VERSION 5.8 ;
BUSBITCHARS "[]" ;
DIVIDERCHAR "/" ;
UNITS
    DATABASE MICRONS 1000 ;
END UNITS

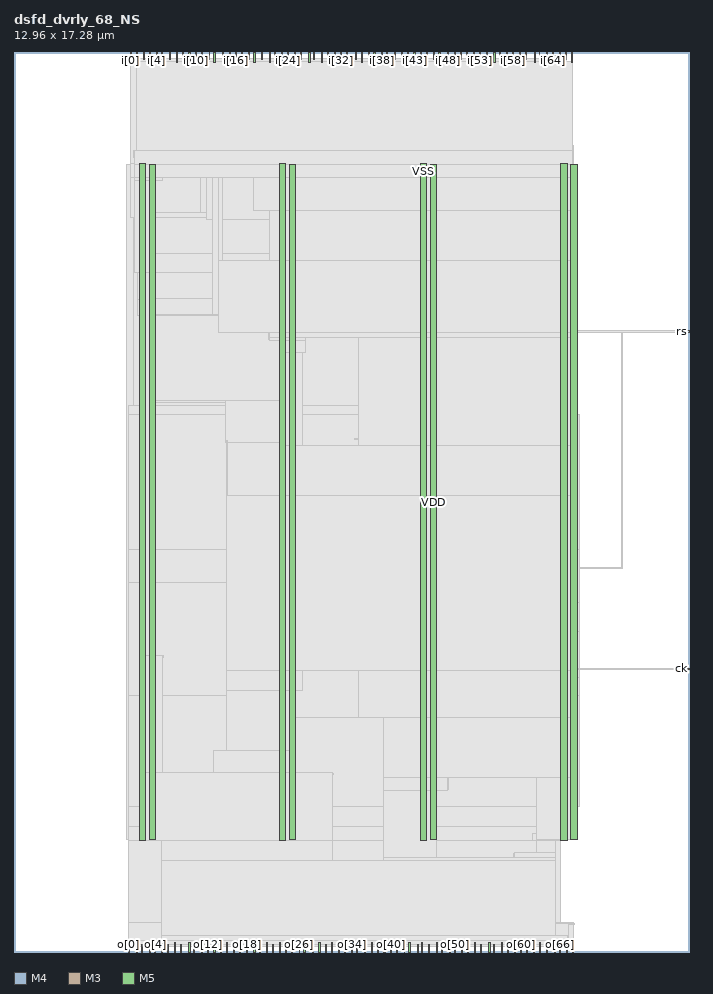
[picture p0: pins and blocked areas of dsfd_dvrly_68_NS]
MACRO dsfd_dvrly_68_NS
  FOREIGN dsfd_dvrly_68_NS 0 0 ;
  CLASS BLOCK ;
  SIZE 12.96 BY 17.28 ;
  PIN ck
    DIRECTION INPUT ;
    USE SIGNAL ;
    PORT
      LAYER M4 ;
        RECT  12.768 5.424 12.96 5.448 ;
    END
  END ck
  PIN ck_o
    DIRECTION OUTPUT ;
    USE SIGNAL ;
    PORT
      LAYER M3 ;
        RECT  10.728 0 10.746 0.144 ;
    END
  END ck_o
  PIN i[0]
    DIRECTION INPUT ;
    USE SIGNAL ;
    PORT
      LAYER M3 ;
        RECT  2.232 17.136 2.25 17.28 ;
    END
  END i[0]
  PIN i[10]
    DIRECTION INPUT ;
    USE SIGNAL ;
    PORT
      LAYER M3 ;
        RECT  3.492 17.136 3.51 17.28 ;
    END
  END i[10]
  PIN i[11]
    DIRECTION INPUT ;
    USE SIGNAL ;
    PORT
      LAYER M5 ;
        RECT  3.6 17.088 3.624 17.28 ;
    END
  END i[11]
  PIN i[12]
    DIRECTION INPUT ;
    USE SIGNAL ;
    PORT
      LAYER M3 ;
        RECT  3.744 17.136 3.762 17.28 ;
    END
  END i[12]
  PIN i[13]
    DIRECTION INPUT ;
    USE SIGNAL ;
    PORT
      LAYER M5 ;
        RECT  3.84 17.088 3.864 17.28 ;
    END
  END i[13]
  PIN i[14]
    DIRECTION INPUT ;
    USE SIGNAL ;
    PORT
      LAYER M3 ;
        RECT  3.996 17.136 4.014 17.28 ;
    END
  END i[14]
  PIN i[15]
    DIRECTION INPUT ;
    USE SIGNAL ;
    PORT
      LAYER M5 ;
        RECT  4.128 17.088 4.152 17.28 ;
    END
  END i[15]
  PIN i[16]
    DIRECTION INPUT ;
    USE SIGNAL ;
    PORT
      LAYER M3 ;
        RECT  4.248 17.136 4.266 17.28 ;
    END
  END i[16]
  PIN i[17]
    DIRECTION INPUT ;
    USE SIGNAL ;
    PORT
      LAYER M5 ;
        RECT  4.368 17.088 4.392 17.28 ;
    END
  END i[17]
  PIN i[18]
    DIRECTION INPUT ;
    USE SIGNAL ;
    PORT
      LAYER M3 ;
        RECT  4.5 17.136 4.518 17.28 ;
    END
  END i[18]
  PIN i[19]
    DIRECTION INPUT ;
    USE SIGNAL ;
    PORT
      LAYER M5 ;
        RECT  4.608 17.088 4.632 17.28 ;
    END
  END i[19]
  PIN i[1]
    DIRECTION INPUT ;
    USE SIGNAL ;
    PORT
      LAYER M5 ;
        RECT  2.352 17.088 2.376 17.28 ;
    END
  END i[1]
  PIN i[20]
    DIRECTION INPUT ;
    USE SIGNAL ;
    PORT
      LAYER M3 ;
        RECT  4.752 17.136 4.77 17.28 ;
    END
  END i[20]
  PIN i[21]
    DIRECTION INPUT ;
    USE SIGNAL ;
    PORT
      LAYER M5 ;
        RECT  4.896 17.088 4.92 17.28 ;
    END
  END i[21]
  PIN i[22]
    DIRECTION INPUT ;
    USE SIGNAL ;
    PORT
      LAYER M3 ;
        RECT  5.004 17.136 5.022 17.28 ;
    END
  END i[22]
  PIN i[23]
    DIRECTION INPUT ;
    USE SIGNAL ;
    PORT
      LAYER M5 ;
        RECT  5.136 17.088 5.16 17.28 ;
    END
  END i[23]
  PIN i[24]
    DIRECTION INPUT ;
    USE SIGNAL ;
    PORT
      LAYER M3 ;
        RECT  5.256 17.136 5.274 17.28 ;
    END
  END i[24]
  PIN i[25]
    DIRECTION INPUT ;
    USE SIGNAL ;
    PORT
      LAYER M5 ;
        RECT  5.376 17.088 5.4 17.28 ;
    END
  END i[25]
  PIN i[26]
    DIRECTION INPUT ;
    USE SIGNAL ;
    PORT
      LAYER M3 ;
        RECT  5.508 17.136 5.526 17.28 ;
    END
  END i[26]
  PIN i[27]
    DIRECTION INPUT ;
    USE SIGNAL ;
    PORT
      LAYER M5 ;
        RECT  5.664 17.088 5.688 17.28 ;
    END
  END i[27]
  PIN i[28]
    DIRECTION INPUT ;
    USE SIGNAL ;
    PORT
      LAYER M3 ;
        RECT  5.76 17.136 5.778 17.28 ;
    END
  END i[28]
  PIN i[29]
    DIRECTION INPUT ;
    USE SIGNAL ;
    PORT
      LAYER M5 ;
        RECT  5.904 17.088 5.928 17.28 ;
    END
  END i[29]
  PIN i[2]
    DIRECTION INPUT ;
    USE SIGNAL ;
    PORT
      LAYER M3 ;
        RECT  2.484 17.136 2.502 17.28 ;
    END
  END i[2]
  PIN i[30]
    DIRECTION INPUT ;
    USE SIGNAL ;
    PORT
      LAYER M3 ;
        RECT  6.012 17.136 6.03 17.28 ;
    END
  END i[30]
  PIN i[31]
    DIRECTION INPUT ;
    USE SIGNAL ;
    PORT
      LAYER M5 ;
        RECT  6.144 17.088 6.168 17.28 ;
    END
  END i[31]
  PIN i[32]
    DIRECTION INPUT ;
    USE SIGNAL ;
    PORT
      LAYER M3 ;
        RECT  6.264 17.136 6.282 17.28 ;
    END
  END i[32]
  PIN i[33]
    DIRECTION INPUT ;
    USE SIGNAL ;
    PORT
      LAYER M5 ;
        RECT  6.384 17.088 6.408 17.28 ;
    END
  END i[33]
  PIN i[34]
    DIRECTION INPUT ;
    USE SIGNAL ;
    PORT
      LAYER M3 ;
        RECT  6.552 17.136 6.57 17.28 ;
    END
  END i[34]
  PIN i[35]
    DIRECTION INPUT ;
    USE SIGNAL ;
    PORT
      LAYER M5 ;
        RECT  6.672 17.088 6.696 17.28 ;
    END
  END i[35]
  PIN i[36]
    DIRECTION INPUT ;
    USE SIGNAL ;
    PORT
      LAYER M3 ;
        RECT  6.804 17.136 6.822 17.28 ;
    END
  END i[36]
  PIN i[37]
    DIRECTION INPUT ;
    USE SIGNAL ;
    PORT
      LAYER M5 ;
        RECT  6.912 17.088 6.936 17.28 ;
    END
  END i[37]
  PIN i[38]
    DIRECTION INPUT ;
    USE SIGNAL ;
    PORT
      LAYER M3 ;
        RECT  7.056 17.136 7.074 17.28 ;
    END
  END i[38]
  PIN i[39]
    DIRECTION INPUT ;
    USE SIGNAL ;
    PORT
      LAYER M5 ;
        RECT  7.152 17.088 7.176 17.28 ;
    END
  END i[39]
  PIN i[3]
    DIRECTION INPUT ;
    USE SIGNAL ;
    PORT
      LAYER M5 ;
        RECT  2.592 17.088 2.616 17.28 ;
    END
  END i[3]
  PIN i[40]
    DIRECTION INPUT ;
    USE SIGNAL ;
    PORT
      LAYER M3 ;
        RECT  7.308 17.136 7.326 17.28 ;
    END
  END i[40]
  PIN i[41]
    DIRECTION INPUT ;
    USE SIGNAL ;
    PORT
      LAYER M5 ;
        RECT  7.44 17.088 7.464 17.28 ;
    END
  END i[41]
  PIN i[42]
    DIRECTION INPUT ;
    USE SIGNAL ;
    PORT
      LAYER M3 ;
        RECT  7.56 17.136 7.578 17.28 ;
    END
  END i[42]
  PIN i[43]
    DIRECTION INPUT ;
    USE SIGNAL ;
    PORT
      LAYER M5 ;
        RECT  7.68 17.088 7.704 17.28 ;
    END
  END i[43]
  PIN i[44]
    DIRECTION INPUT ;
    USE SIGNAL ;
    PORT
      LAYER M3 ;
        RECT  7.812 17.136 7.83 17.28 ;
    END
  END i[44]
  PIN i[45]
    DIRECTION INPUT ;
    USE SIGNAL ;
    PORT
      LAYER M5 ;
        RECT  7.92 17.088 7.944 17.28 ;
    END
  END i[45]
  PIN i[46]
    DIRECTION INPUT ;
    USE SIGNAL ;
    PORT
      LAYER M3 ;
        RECT  8.064 17.136 8.082 17.28 ;
    END
  END i[46]
  PIN i[47]
    DIRECTION INPUT ;
    USE SIGNAL ;
    PORT
      LAYER M5 ;
        RECT  8.16 17.088 8.184 17.28 ;
    END
  END i[47]
  PIN i[48]
    DIRECTION INPUT ;
    USE SIGNAL ;
    PORT
      LAYER M3 ;
        RECT  8.316 17.136 8.334 17.28 ;
    END
  END i[48]
  PIN i[49]
    DIRECTION INPUT ;
    USE SIGNAL ;
    PORT
      LAYER M5 ;
        RECT  8.448 17.088 8.472 17.28 ;
    END
  END i[49]
  PIN i[4]
    DIRECTION INPUT ;
    USE SIGNAL ;
    PORT
      LAYER M3 ;
        RECT  2.736 17.136 2.754 17.28 ;
    END
  END i[4]
  PIN i[50]
    DIRECTION INPUT ;
    USE SIGNAL ;
    PORT
      LAYER M3 ;
        RECT  8.568 17.136 8.586 17.28 ;
    END
  END i[50]
  PIN i[51]
    DIRECTION INPUT ;
    USE SIGNAL ;
    PORT
      LAYER M5 ;
        RECT  8.688 17.088 8.712 17.28 ;
    END
  END i[51]
  PIN i[52]
    DIRECTION INPUT ;
    USE SIGNAL ;
    PORT
      LAYER M3 ;
        RECT  8.82 17.136 8.838 17.28 ;
    END
  END i[52]
  PIN i[53]
    DIRECTION INPUT ;
    USE SIGNAL ;
    PORT
      LAYER M5 ;
        RECT  8.928 17.088 8.952 17.28 ;
    END
  END i[53]
  PIN i[54]
    DIRECTION INPUT ;
    USE SIGNAL ;
    PORT
      LAYER M3 ;
        RECT  9.072 17.136 9.09 17.28 ;
    END
  END i[54]
  PIN i[55]
    DIRECTION INPUT ;
    USE SIGNAL ;
    PORT
      LAYER M5 ;
        RECT  9.216 17.088 9.24 17.28 ;
    END
  END i[55]
  PIN i[56]
    DIRECTION INPUT ;
    USE SIGNAL ;
    PORT
      LAYER M3 ;
        RECT  9.324 17.136 9.342 17.28 ;
    END
  END i[56]
  PIN i[57]
    DIRECTION INPUT ;
    USE SIGNAL ;
    PORT
      LAYER M5 ;
        RECT  9.456 17.088 9.48 17.28 ;
    END
  END i[57]
  PIN i[58]
    DIRECTION INPUT ;
    USE SIGNAL ;
    PORT
      LAYER M3 ;
        RECT  9.576 17.136 9.594 17.28 ;
    END
  END i[58]
  PIN i[59]
    DIRECTION INPUT ;
    USE SIGNAL ;
    PORT
      LAYER M5 ;
        RECT  9.696 17.088 9.72 17.28 ;
    END
  END i[59]
  PIN i[5]
    DIRECTION INPUT ;
    USE SIGNAL ;
    PORT
      LAYER M5 ;
        RECT  2.832 17.088 2.856 17.28 ;
    END
  END i[5]
  PIN i[60]
    DIRECTION INPUT ;
    USE SIGNAL ;
    PORT
      LAYER M3 ;
        RECT  9.828 17.136 9.846 17.28 ;
    END
  END i[60]
  PIN i[61]
    DIRECTION INPUT ;
    USE SIGNAL ;
    PORT
      LAYER M5 ;
        RECT  9.984 17.088 10.008 17.28 ;
    END
  END i[61]
  PIN i[62]
    DIRECTION INPUT ;
    USE SIGNAL ;
    PORT
      LAYER M3 ;
        RECT  10.08 17.136 10.098 17.28 ;
    END
  END i[62]
  PIN i[63]
    DIRECTION INPUT ;
    USE SIGNAL ;
    PORT
      LAYER M5 ;
        RECT  10.224 17.088 10.248 17.28 ;
    END
  END i[63]
  PIN i[64]
    DIRECTION INPUT ;
    USE SIGNAL ;
    PORT
      LAYER M3 ;
        RECT  10.332 17.136 10.35 17.28 ;
    END
  END i[64]
  PIN i[65]
    DIRECTION INPUT ;
    USE SIGNAL ;
    PORT
      LAYER M5 ;
        RECT  10.464 17.088 10.488 17.28 ;
    END
  END i[65]
  PIN i[66]
    DIRECTION INPUT ;
    USE SIGNAL ;
    PORT
      LAYER M3 ;
        RECT  10.584 17.136 10.602 17.28 ;
    END
  END i[66]
  PIN i[67]
    DIRECTION INPUT ;
    USE SIGNAL ;
    PORT
      LAYER M5 ;
        RECT  10.704 17.088 10.728 17.28 ;
    END
  END i[67]
  PIN i[6]
    DIRECTION INPUT ;
    USE SIGNAL ;
    PORT
      LAYER M3 ;
        RECT  2.988 17.136 3.006 17.28 ;
    END
  END i[6]
  PIN i[7]
    DIRECTION INPUT ;
    USE SIGNAL ;
    PORT
      LAYER M5 ;
        RECT  3.12 17.088 3.144 17.28 ;
    END
  END i[7]
  PIN i[8]
    DIRECTION INPUT ;
    USE SIGNAL ;
    PORT
      LAYER M3 ;
        RECT  3.24 17.136 3.258 17.28 ;
    END
  END i[8]
  PIN i[9]
    DIRECTION INPUT ;
    USE SIGNAL ;
    PORT
      LAYER M5 ;
        RECT  3.36 17.088 3.384 17.28 ;
    END
  END i[9]
  PIN o[0]
    DIRECTION OUTPUT ;
    USE SIGNAL ;
    PORT
      LAYER M3 ;
        RECT  2.196 0 2.214 0.144 ;
    END
  END o[0]
  PIN o[10]
    DIRECTION OUTPUT ;
    USE SIGNAL ;
    PORT
      LAYER M3 ;
        RECT  3.456 0 3.474 0.144 ;
    END
  END o[10]
  PIN o[11]
    DIRECTION OUTPUT ;
    USE SIGNAL ;
    PORT
      LAYER M5 ;
        RECT  3.6 0 3.624 0.192 ;
    END
  END o[11]
  PIN o[12]
    DIRECTION OUTPUT ;
    USE SIGNAL ;
    PORT
      LAYER M3 ;
        RECT  3.708 0 3.726 0.144 ;
    END
  END o[12]
  PIN o[13]
    DIRECTION OUTPUT ;
    USE SIGNAL ;
    PORT
      LAYER M5 ;
        RECT  3.84 0 3.864 0.192 ;
    END
  END o[13]
  PIN o[14]
    DIRECTION OUTPUT ;
    USE SIGNAL ;
    PORT
      LAYER M3 ;
        RECT  3.96 0 3.978 0.144 ;
    END
  END o[14]
  PIN o[15]
    DIRECTION OUTPUT ;
    USE SIGNAL ;
    PORT
      LAYER M5 ;
        RECT  4.08 0 4.104 0.192 ;
    END
  END o[15]
  PIN o[16]
    DIRECTION OUTPUT ;
    USE SIGNAL ;
    PORT
      LAYER M3 ;
        RECT  4.212 0 4.23 0.144 ;
    END
  END o[16]
  PIN o[17]
    DIRECTION OUTPUT ;
    USE SIGNAL ;
    PORT
      LAYER M5 ;
        RECT  4.32 0 4.344 0.192 ;
    END
  END o[17]
  PIN o[18]
    DIRECTION OUTPUT ;
    USE SIGNAL ;
    PORT
      LAYER M3 ;
        RECT  4.464 0 4.482 0.144 ;
    END
  END o[18]
  PIN o[19]
    DIRECTION OUTPUT ;
    USE SIGNAL ;
    PORT
      LAYER M5 ;
        RECT  4.608 0 4.632 0.192 ;
    END
  END o[19]
  PIN o[1]
    DIRECTION OUTPUT ;
    USE SIGNAL ;
    PORT
      LAYER M5 ;
        RECT  2.352 0 2.376 0.192 ;
    END
  END o[1]
  PIN o[20]
    DIRECTION OUTPUT ;
    USE SIGNAL ;
    PORT
      LAYER M3 ;
        RECT  4.716 0 4.734 0.144 ;
    END
  END o[20]
  PIN o[21]
    DIRECTION OUTPUT ;
    USE SIGNAL ;
    PORT
      LAYER M5 ;
        RECT  4.848 0 4.872 0.192 ;
    END
  END o[21]
  PIN o[22]
    DIRECTION OUTPUT ;
    USE SIGNAL ;
    PORT
      LAYER M3 ;
        RECT  4.968 0 4.986 0.144 ;
    END
  END o[22]
  PIN o[23]
    DIRECTION OUTPUT ;
    USE SIGNAL ;
    PORT
      LAYER M5 ;
        RECT  5.088 0 5.112 0.192 ;
    END
  END o[23]
  PIN o[24]
    DIRECTION OUTPUT ;
    USE SIGNAL ;
    PORT
      LAYER M3 ;
        RECT  5.22 0 5.238 0.144 ;
    END
  END o[24]
  PIN o[25]
    DIRECTION OUTPUT ;
    USE SIGNAL ;
    PORT
      LAYER M5 ;
        RECT  5.328 0 5.352 0.192 ;
    END
  END o[25]
  PIN o[26]
    DIRECTION OUTPUT ;
    USE SIGNAL ;
    PORT
      LAYER M3 ;
        RECT  5.472 0 5.49 0.144 ;
    END
  END o[26]
  PIN o[27]
    DIRECTION OUTPUT ;
    USE SIGNAL ;
    PORT
      LAYER M5 ;
        RECT  5.568 0 5.592 0.192 ;
    END
  END o[27]
  PIN o[28]
    DIRECTION OUTPUT ;
    USE SIGNAL ;
    PORT
      LAYER M3 ;
        RECT  5.724 0 5.742 0.144 ;
    END
  END o[28]
  PIN o[29]
    DIRECTION OUTPUT ;
    USE SIGNAL ;
    PORT
      LAYER M5 ;
        RECT  5.856 0 5.88 0.192 ;
    END
  END o[29]
  PIN o[2]
    DIRECTION OUTPUT ;
    USE SIGNAL ;
    PORT
      LAYER M3 ;
        RECT  2.448 0 2.466 0.144 ;
    END
  END o[2]
  PIN o[30]
    DIRECTION OUTPUT ;
    USE SIGNAL ;
    PORT
      LAYER M3 ;
        RECT  5.976 0 5.994 0.144 ;
    END
  END o[30]
  PIN o[31]
    DIRECTION OUTPUT ;
    USE SIGNAL ;
    PORT
      LAYER M5 ;
        RECT  6.096 0 6.12 0.192 ;
    END
  END o[31]
  PIN o[32]
    DIRECTION OUTPUT ;
    USE SIGNAL ;
    PORT
      LAYER M3 ;
        RECT  6.228 0 6.246 0.144 ;
    END
  END o[32]
  PIN o[33]
    DIRECTION OUTPUT ;
    USE SIGNAL ;
    PORT
      LAYER M5 ;
        RECT  6.336 0 6.36 0.192 ;
    END
  END o[33]
  PIN o[34]
    DIRECTION OUTPUT ;
    USE SIGNAL ;
    PORT
      LAYER M3 ;
        RECT  6.48 0 6.498 0.144 ;
    END
  END o[34]
  PIN o[35]
    DIRECTION OUTPUT ;
    USE SIGNAL ;
    PORT
      LAYER M5 ;
        RECT  6.576 0 6.6 0.192 ;
    END
  END o[35]
  PIN o[36]
    DIRECTION OUTPUT ;
    USE SIGNAL ;
    PORT
      LAYER M3 ;
        RECT  6.732 0 6.75 0.144 ;
    END
  END o[36]
  PIN o[37]
    DIRECTION OUTPUT ;
    USE SIGNAL ;
    PORT
      LAYER M5 ;
        RECT  6.864 0 6.888 0.192 ;
    END
  END o[37]
  PIN o[38]
    DIRECTION OUTPUT ;
    USE SIGNAL ;
    PORT
      LAYER M3 ;
        RECT  6.984 0 7.002 0.144 ;
    END
  END o[38]
  PIN o[39]
    DIRECTION OUTPUT ;
    USE SIGNAL ;
    PORT
      LAYER M5 ;
        RECT  7.104 0 7.128 0.192 ;
    END
  END o[39]
  PIN o[3]
    DIRECTION OUTPUT ;
    USE SIGNAL ;
    PORT
      LAYER M5 ;
        RECT  2.592 0 2.616 0.192 ;
    END
  END o[3]
  PIN o[40]
    DIRECTION OUTPUT ;
    USE SIGNAL ;
    PORT
      LAYER M3 ;
        RECT  7.236 0 7.254 0.144 ;
    END
  END o[40]
  PIN o[41]
    DIRECTION OUTPUT ;
    USE SIGNAL ;
    PORT
      LAYER M5 ;
        RECT  7.344 0 7.368 0.192 ;
    END
  END o[41]
  PIN o[42]
    DIRECTION OUTPUT ;
    USE SIGNAL ;
    PORT
      LAYER M3 ;
        RECT  7.488 0 7.506 0.144 ;
    END
  END o[42]
  PIN o[43]
    DIRECTION OUTPUT ;
    USE SIGNAL ;
    PORT
      LAYER M5 ;
        RECT  7.584 0 7.608 0.192 ;
    END
  END o[43]
  PIN o[44]
    DIRECTION OUTPUT ;
    USE SIGNAL ;
    PORT
      LAYER M3 ;
        RECT  7.74 0 7.758 0.144 ;
    END
  END o[44]
  PIN o[45]
    DIRECTION OUTPUT ;
    USE SIGNAL ;
    PORT
      LAYER M5 ;
        RECT  7.824 0 7.848 0.192 ;
    END
  END o[45]
  PIN o[46]
    DIRECTION OUTPUT ;
    USE SIGNAL ;
    PORT
      LAYER M3 ;
        RECT  7.956 0 7.974 0.144 ;
    END
  END o[46]
  PIN o[47]
    DIRECTION OUTPUT ;
    USE SIGNAL ;
    PORT
      LAYER M5 ;
        RECT  8.112 0 8.136 0.192 ;
    END
  END o[47]
  PIN o[48]
    DIRECTION OUTPUT ;
    USE SIGNAL ;
    PORT
      LAYER M3 ;
        RECT  8.208 0 8.226 0.144 ;
    END
  END o[48]
  PIN o[49]
    DIRECTION OUTPUT ;
    USE SIGNAL ;
    PORT
      LAYER M5 ;
        RECT  8.352 0 8.376 0.192 ;
    END
  END o[49]
  PIN o[4]
    DIRECTION OUTPUT ;
    USE SIGNAL ;
    PORT
      LAYER M3 ;
        RECT  2.7 0 2.718 0.144 ;
    END
  END o[4]
  PIN o[50]
    DIRECTION OUTPUT ;
    USE SIGNAL ;
    PORT
      LAYER M3 ;
        RECT  8.46 0 8.478 0.144 ;
    END
  END o[50]
  PIN o[51]
    DIRECTION OUTPUT ;
    USE SIGNAL ;
    PORT
      LAYER M5 ;
        RECT  8.592 0 8.616 0.192 ;
    END
  END o[51]
  PIN o[52]
    DIRECTION OUTPUT ;
    USE SIGNAL ;
    PORT
      LAYER M3 ;
        RECT  8.712 0 8.73 0.144 ;
    END
  END o[52]
  PIN o[53]
    DIRECTION OUTPUT ;
    USE SIGNAL ;
    PORT
      LAYER M5 ;
        RECT  8.832 0 8.856 0.192 ;
    END
  END o[53]
  PIN o[54]
    DIRECTION OUTPUT ;
    USE SIGNAL ;
    PORT
      LAYER M3 ;
        RECT  8.964 0 8.982 0.144 ;
    END
  END o[54]
  PIN o[55]
    DIRECTION OUTPUT ;
    USE SIGNAL ;
    PORT
      LAYER M5 ;
        RECT  9.12 0 9.144 0.192 ;
    END
  END o[55]
  PIN o[56]
    DIRECTION OUTPUT ;
    USE SIGNAL ;
    PORT
      LAYER M3 ;
        RECT  9.216 0 9.234 0.144 ;
    END
  END o[56]
  PIN o[57]
    DIRECTION OUTPUT ;
    USE SIGNAL ;
    PORT
      LAYER M5 ;
        RECT  9.36 0 9.384 0.192 ;
    END
  END o[57]
  PIN o[58]
    DIRECTION OUTPUT ;
    USE SIGNAL ;
    PORT
      LAYER M3 ;
        RECT  9.468 0 9.486 0.144 ;
    END
  END o[58]
  PIN o[59]
    DIRECTION OUTPUT ;
    USE SIGNAL ;
    PORT
      LAYER M5 ;
        RECT  9.6 0 9.624 0.192 ;
    END
  END o[59]
  PIN o[5]
    DIRECTION OUTPUT ;
    USE SIGNAL ;
    PORT
      LAYER M5 ;
        RECT  2.832 0 2.856 0.192 ;
    END
  END o[5]
  PIN o[60]
    DIRECTION OUTPUT ;
    USE SIGNAL ;
    PORT
      LAYER M3 ;
        RECT  9.72 0 9.738 0.144 ;
    END
  END o[60]
  PIN o[61]
    DIRECTION OUTPUT ;
    USE SIGNAL ;
    PORT
      LAYER M5 ;
        RECT  9.84 0 9.864 0.192 ;
    END
  END o[61]
  PIN o[62]
    DIRECTION OUTPUT ;
    USE SIGNAL ;
    PORT
      LAYER M3 ;
        RECT  9.972 0 9.99 0.144 ;
    END
  END o[62]
  PIN o[63]
    DIRECTION OUTPUT ;
    USE SIGNAL ;
    PORT
      LAYER M5 ;
        RECT  10.08 0 10.104 0.192 ;
    END
  END o[63]
  PIN o[64]
    DIRECTION OUTPUT ;
    USE SIGNAL ;
    PORT
      LAYER M3 ;
        RECT  10.224 0 10.242 0.144 ;
    END
  END o[64]
  PIN o[65]
    DIRECTION OUTPUT ;
    USE SIGNAL ;
    PORT
      LAYER M5 ;
        RECT  10.368 0 10.392 0.192 ;
    END
  END o[65]
  PIN o[66]
    DIRECTION OUTPUT ;
    USE SIGNAL ;
    PORT
      LAYER M3 ;
        RECT  10.476 0 10.494 0.144 ;
    END
  END o[66]
  PIN o[67]
    DIRECTION OUTPUT ;
    USE SIGNAL ;
    PORT
      LAYER M5 ;
        RECT  10.608 0 10.632 0.192 ;
    END
  END o[67]
  PIN o[6]
    DIRECTION OUTPUT ;
    USE SIGNAL ;
    PORT
      LAYER M3 ;
        RECT  2.952 0 2.97 0.144 ;
    END
  END o[6]
  PIN o[7]
    DIRECTION OUTPUT ;
    USE SIGNAL ;
    PORT
      LAYER M5 ;
        RECT  3.072 0 3.096 0.192 ;
    END
  END o[7]
  PIN o[8]
    DIRECTION OUTPUT ;
    USE SIGNAL ;
    PORT
      LAYER M3 ;
        RECT  3.204 0 3.222 0.144 ;
    END
  END o[8]
  PIN o[9]
    DIRECTION OUTPUT ;
    USE SIGNAL ;
    PORT
      LAYER M5 ;
        RECT  3.36 0 3.384 0.192 ;
    END
  END o[9]
  PIN rs
    DIRECTION INPUT ;
    USE SIGNAL ;
    PORT
      LAYER M4 ;
        RECT  12.768 11.904 12.96 11.928 ;
    END
  END rs
  PIN VDD
    DIRECTION INOUT ;
    USE POWER ;
    PORT
      LAYER M5 ;
        RECT  10.692 2.151 10.812 15.129 ;
        RECT  7.992 2.151 8.112 15.129 ;
        RECT  5.292 2.151 5.412 15.129 ;
        RECT  2.592 2.151 2.712 15.129 ;
    END
  END VDD
  PIN VSS
    DIRECTION INOUT ;
    USE GROUND ;
    PORT
      LAYER M5 ;
        RECT  10.5 2.137 10.62 15.143 ;
        RECT  7.8 2.137 7.92 15.143 ;
        RECT  5.1 2.137 5.22 15.143 ;
        RECT  2.4 2.137 2.52 15.143 ;
    END
  END VSS
  OBS
    LAYER RVTN ;
     RECT  2.16 2.16 10.8 2.295 ;
     RECT  2.16 2.565 10.8 2.835 ;
     RECT  2.16 3.105 10.8 3.375 ;
     RECT  2.16 3.645 10.8 3.915 ;
     RECT  2.16 4.185 10.8 4.455 ;
     RECT  2.16 4.725 10.8 4.995 ;
     RECT  2.16 5.265 10.8 5.535 ;
     RECT  2.16 5.805 10.8 6.075 ;
     RECT  2.16 6.345 10.8 6.615 ;
     RECT  2.16 6.885 10.8 7.155 ;
     RECT  2.16 7.425 10.8 7.695 ;
     RECT  2.16 7.965 10.8 8.235 ;
     RECT  2.16 8.505 10.8 8.775 ;
     RECT  2.16 9.045 10.8 9.315 ;
     RECT  2.16 9.585 10.8 9.855 ;
     RECT  2.16 10.125 10.8 10.395 ;
     RECT  2.16 10.665 10.8 10.935 ;
     RECT  2.16 11.205 10.8 11.475 ;
     RECT  2.16 11.745 10.8 12.015 ;
     RECT  2.16 12.285 10.8 12.555 ;
     RECT  2.16 12.825 10.8 13.095 ;
     RECT  2.16 13.365 10.8 13.635 ;
     RECT  2.16 13.905 10.8 14.175 ;
     RECT  2.16 14.445 10.8 14.715 ;
     RECT  2.16 14.985 10.8 15.12 ;
    LAYER RVTP ;
     RECT  2.16 2.295 10.8 2.565 ;
     RECT  2.16 2.835 10.8 3.105 ;
     RECT  2.16 3.375 10.8 3.645 ;
     RECT  2.16 3.915 10.8 4.185 ;
     RECT  2.16 4.455 10.8 4.725 ;
     RECT  2.16 4.995 10.8 5.265 ;
     RECT  2.16 5.535 10.8 5.805 ;
     RECT  2.16 6.075 10.8 6.345 ;
     RECT  2.16 6.615 10.8 6.885 ;
     RECT  2.16 7.155 10.8 7.425 ;
     RECT  2.16 7.695 10.8 7.965 ;
     RECT  2.16 8.235 10.8 8.505 ;
     RECT  2.16 8.775 10.8 9.045 ;
     RECT  2.16 9.315 10.8 9.585 ;
     RECT  2.16 9.855 10.8 10.125 ;
     RECT  2.16 10.395 10.8 10.665 ;
     RECT  2.16 10.935 10.8 11.205 ;
     RECT  2.16 11.475 10.8 11.745 ;
     RECT  2.16 12.015 10.8 12.285 ;
     RECT  2.16 12.555 10.8 12.825 ;
     RECT  2.16 13.095 10.8 13.365 ;
     RECT  2.16 13.635 10.8 13.905 ;
     RECT  2.16 14.175 10.8 14.445 ;
     RECT  2.16 14.715 10.8 14.985 ;
    LAYER M1 ;
     RECT  2.16 2.151 10.8 15.129 ;
    LAYER M2 ;
     RECT  2.16 2.151 2.299 15.129 ;
     RECT  2.299 2.151 2.507 15.21 ;
     RECT  2.507 2.151 3.739 15.129 ;
     RECT  2.335 0.144 3.955 0.162 ;
     RECT  3.955 0.144 4.307 0.198 ;
     RECT  4.307 0.144 4.487 0.162 ;
     RECT  3.739 2.151 5.099 15.174 ;
     RECT  5.215 0.144 5.459 0.162 ;
     RECT  5.099 2.151 6.223 15.129 ;
     RECT  5.467 0.216 6.467 0.234 ;
     RECT  6.223 2.106 6.755 15.129 ;
     RECT  6.727 0.144 6.827 0.162 ;
     RECT  6.755 2.151 7.735 15.129 ;
     RECT  7.735 2.151 7.835 15.21 ;
     RECT  7.835 2.151 8.267 15.174 ;
     RECT  7.771 0.144 8.483 0.162 ;
     RECT  9.211 0.144 10.247 0.162 ;
     RECT  10.291 17.19 10.327 17.208 ;
     RECT  10.327 17.118 10.427 17.208 ;
     RECT  8.267 2.151 10.471 15.129 ;
     RECT  10.471 2.151 10.607 15.21 ;
     RECT  10.607 2.151 10.8 15.129 ;
     RECT  10.8 2.421 10.812 14.859 ;
     RECT  10.812 2.808 10.859 2.826 ;
     RECT  10.812 10.296 10.859 10.314 ;
     RECT  10.812 7.362 11.687 7.38 ;
    LAYER M3 ;
     RECT  2.196 0.108 10.746 0.557 ;
     RECT  2.196 0.557 10.494 2.143 ;
     RECT  2.196 2.143 10.605 2.413 ;
     RECT  2.196 2.413 10.797 2.803 ;
     RECT  2.196 2.803 10.854 4.919 ;
     RECT  7.704 4.919 10.854 5.261 ;
     RECT  7.704 5.261 8.154 6.151 ;
     RECT  8.964 5.261 10.854 6.151 ;
     RECT  7.704 6.151 10.854 6.719 ;
     RECT  2.196 4.919 6.93 7.087 ;
     RECT  2.196 7.087 7.002 7.735 ;
     RECT  7.815 6.719 10.854 7.735 ;
     RECT  2.196 7.735 10.854 10.319 ;
     RECT  2.196 10.319 10.797 10.499 ;
     RECT  11.664 7.357 11.682 11.933 ;
     RECT  2.415 10.499 10.797 12.217 ;
     RECT  2.376 12.217 10.797 13.051 ;
     RECT  2.34 13.051 10.797 13.405 ;
     RECT  2.304 13.405 10.797 14.107 ;
     RECT  2.232 14.107 10.797 14.867 ;
     RECT  2.232 14.867 10.605 15.137 ;
     RECT  2.232 15.137 10.602 17.148 ;
     RECT  10.296 17.148 10.422 17.213 ;
    LAYER M4 ;
     RECT  2.293 15.36 2.3 15.384 ;
     RECT  2.293 13.056 2.365 13.08 ;
     RECT  2.365 12.528 2.408 13.08 ;
     RECT  2.3 15.264 2.408 15.384 ;
     RECT  2.408 2.148 2.512 15.384 ;
     RECT  2.512 2.418 2.627 15.384 ;
     RECT  2.627 2.418 2.704 14.904 ;
     RECT  2.704 5.664 2.867 5.688 ;
     RECT  2.321 0.192 3.041 0.216 ;
     RECT  2.365 16.56 3.155 16.584 ;
     RECT  3.041 0.192 3.341 0.264 ;
     RECT  2.704 14.208 3.589 14.904 ;
     RECT  3.589 14.208 3.697 15.048 ;
     RECT  3.697 14.064 3.701 15.048 ;
     RECT  2.704 12.24 3.805 12.552 ;
     RECT  3.701 14.064 3.805 14.904 ;
     RECT  2.704 3.408 3.829 3.432 ;
     RECT  3.805 12.24 3.925 14.904 ;
     RECT  3.829 3.408 3.953 3.864 ;
     RECT  3.925 11.904 4.012 14.904 ;
     RECT  4.012 11.904 4.061 12.984 ;
     RECT  2.704 10.56 4.069 10.584 ;
     RECT  3.349 0.288 4.309 0.312 ;
     RECT  4.309 0.192 4.805 0.312 ;
     RECT  4.061 11.904 4.885 12.84 ;
     RECT  4.805 0.192 4.889 1.176 ;
     RECT  3.953 3.84 5.108 3.864 ;
     RECT  4.885 5.04 5.108 5.064 ;
     RECT  4.981 8.736 5.108 8.76 ;
     RECT  4.069 9.792 5.108 10.584 ;
     RECT  4.885 11.76 5.108 12.84 ;
     RECT  4.012 14.064 5.108 14.904 ;
     RECT  4.889 0.192 5.123 0.312 ;
     RECT  5.108 2.148 5.125 15.132 ;
     RECT  5.125 2.148 5.317 15.288 ;
     RECT  5.317 1.728 5.404 15.288 ;
     RECT  5.123 0.192 5.537 0.264 ;
     RECT  5.404 11.52 5.555 15.288 ;
     RECT  5.555 11.52 5.603 13.704 ;
     RECT  5.555 14.784 5.603 15.288 ;
     RECT  5.537 0.192 5.825 0.216 ;
     RECT  5.404 3.408 6.131 3.432 ;
     RECT  5.404 9.696 6.275 9.72 ;
     RECT  6.109 16.56 6.419 16.584 ;
     RECT  5.603 11.808 6.605 13.704 ;
     RECT  5.603 14.784 6.605 14.904 ;
     RECT  6.605 11.808 6.829 14.904 ;
     RECT  6.829 11.808 7.109 15.096 ;
     RECT  6.541 9.84 7.381 9.864 ;
     RECT  7.325 0.576 7.409 0.6 ;
     RECT  7.381 9.072 7.573 9.864 ;
     RECT  7.109 11.376 7.573 15.096 ;
     RECT  7.573 9.072 7.765 15.096 ;
     RECT  5.404 1.728 7.808 1.752 ;
     RECT  7.585 3.408 7.808 3.432 ;
     RECT  5.404 4.512 7.808 5.448 ;
     RECT  7.765 9.072 7.808 15.288 ;
     RECT  7.808 1.728 7.955 15.288 ;
     RECT  7.955 1.728 8.104 15.24 ;
     RECT  8.104 3.12 8.165 5.304 ;
     RECT  8.165 3.12 8.339 4.296 ;
     RECT  8.104 9.072 8.387 15.24 ;
     RECT  8.387 9.072 9.097 9.384 ;
     RECT  8.339 3.36 9.133 4.296 ;
     RECT  8.165 5.28 9.133 5.304 ;
     RECT  9.097 8.544 9.308 9.384 ;
     RECT  9.308 7.632 9.389 9.384 ;
     RECT  9.389 7.632 9.395 7.656 ;
     RECT  8.387 10.416 9.493 14.904 ;
     RECT  9.133 3.36 9.529 5.304 ;
     RECT  9.493 10.416 9.533 15.432 ;
     RECT  8.104 1.728 9.589 1.8 ;
     RECT  9.589 1.728 9.677 1.896 ;
     RECT  9.685 16.56 9.772 16.584 ;
     RECT  8.701 0.288 9.809 0.312 ;
     RECT  9.809 0.288 9.893 1.176 ;
     RECT  9.389 8.832 9.961 9.384 ;
     RECT  9.533 10.416 9.961 11.496 ;
     RECT  9.961 2.148 10.105 2.28 ;
     RECT  9.529 3.36 10.105 5.688 ;
     RECT  9.533 12.528 10.249 15.432 ;
     RECT  10.105 2.148 10.508 5.688 ;
     RECT  10.357 6.864 10.508 6.888 ;
     RECT  9.961 8.832 10.508 11.496 ;
     RECT  10.249 12.528 10.508 15.48 ;
     RECT  10.508 2.148 10.612 15.48 ;
     RECT  9.893 0.288 10.643 0.552 ;
     RECT  10.612 2.418 10.739 15.48 ;
     RECT  10.643 0.528 10.757 0.552 ;
     RECT  10.739 2.418 10.804 14.862 ;
     RECT  10.804 5.424 12.78 5.448 ;
     RECT  10.804 11.904 12.78 11.928 ;
    LAYER M5 ;
     RECT  2.352 0.144 10.632 0.227 ;
     RECT  2.832 0.227 10.632 0.323 ;
     RECT  2.832 0.323 10.392 1.763 ;
     RECT  7.104 1.763 10.392 1.811 ;
     RECT  9.6 1.811 10.392 1.907 ;
     RECT  2.832 1.763 6.12 2.137 ;
     RECT  10.032 1.907 10.392 2.137 ;
     RECT  10.032 2.137 10.62 2.151 ;
     RECT  7.104 1.811 8.112 3.109 ;
     RECT  7.104 3.109 8.328 3.349 ;
     RECT  10.032 2.151 10.812 3.349 ;
     RECT  2.4 2.137 6.12 3.443 ;
     RECT  3.84 3.443 5.412 3.875 ;
     RECT  7.104 3.349 10.812 4.501 ;
     RECT  4.08 3.875 5.412 5.029 ;
     RECT  4.08 5.029 5.544 5.413 ;
     RECT  6.624 4.501 10.812 5.413 ;
     RECT  2.4 3.443 2.856 5.699 ;
     RECT  4.08 5.413 10.812 8.771 ;
     RECT  5.1 8.771 10.812 9.731 ;
     RECT  4.08 8.771 4.104 9.827 ;
     RECT  5.1 9.731 5.544 11.509 ;
     RECT  5.1 11.509 5.592 11.749 ;
     RECT  4.896 11.749 5.592 11.797 ;
     RECT  6.624 9.731 10.812 11.797 ;
     RECT  4.896 11.797 10.812 11.893 ;
     RECT  2.4 5.699 2.712 13.045 ;
     RECT  3.936 11.893 10.812 13.283 ;
     RECT  4.896 13.283 10.812 14.245 ;
     RECT  2.304 13.045 2.712 14.821 ;
     RECT  2.304 14.821 2.856 14.869 ;
     RECT  4.608 14.245 10.812 14.869 ;
     RECT  2.304 14.869 10.812 15.129 ;
     RECT  2.304 15.129 10.728 15.395 ;
     RECT  2.352 15.395 10.728 17.104 ;
  END
END dsfd_dvrly_68_NS
END LIBRARY
